One B-rep face of a CAD part: STEP entity #988.
In plain terms, the planar face has unit normal (1, 0, 0).
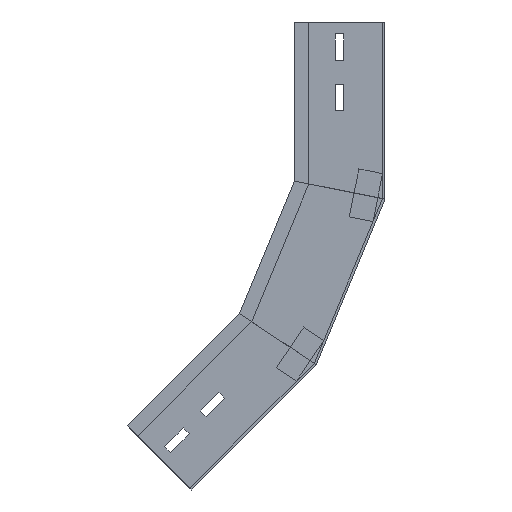
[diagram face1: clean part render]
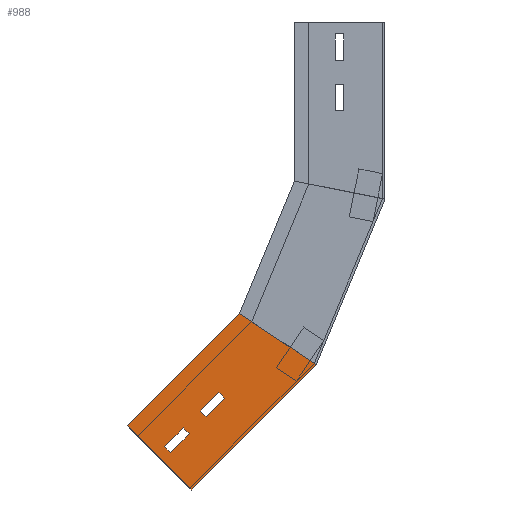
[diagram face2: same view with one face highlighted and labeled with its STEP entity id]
Its self-contained STEP definition (entity closure, numbers rounded to 3 decimals):
#8 = ORIENTED_EDGE ( 'NONE', *, *, #120, .T. ) ;
#31 = VERTEX_POINT ( 'NONE', #232 ) ;
#37 = LINE ( 'NONE', #870, #154 ) ;
#45 = CARTESIAN_POINT ( 'NONE',  ( 0., 0., 0. ) ) ;
#56 = ORIENTED_EDGE ( 'NONE', *, *, #422, .T. ) ;
#59 = CARTESIAN_POINT ( 'NONE',  ( 0., 0., 0. ) ) ;
#78 = DIRECTION ( 'NONE',  ( 0., 0., -1. ) ) ;
#106 = LINE ( 'NONE', #902, #187 ) ;
#120 = EDGE_CURVE ( 'NONE', #785, #31, #37, .T. ) ;
#132 = VECTOR ( 'NONE', #1437, 1000. ) ;
#133 = CARTESIAN_POINT ( 'NONE',  ( 0., 0., 0. ) ) ;
#145 = EDGE_CURVE ( 'NONE', #31, #945, #1111, .T. ) ;
#154 = VECTOR ( 'NONE', #386, 1000. ) ;
#184 = EDGE_CURVE ( 'NONE', #867, #553, #193, .T. ) ;
#185 = EDGE_CURVE ( 'NONE', #945, #330, #884, .T. ) ;
#187 = VECTOR ( 'NONE', #1474, 1000. ) ;
#193 = LINE ( 'NONE', #521, #1269 ) ;
#232 = CARTESIAN_POINT ( 'NONE',  ( 0., 34., -51.505 ) ) ;
#247 = EDGE_CURVE ( 'NONE', #1262, #1181, #1089, .T. ) ;
#288 = PLANE ( 'NONE',  #1145 ) ;
#316 = LINE ( 'NONE', #791, #685 ) ;
#330 = VERTEX_POINT ( 'NONE', #1309 ) ;
#370 = FACE_BOUND ( 'NONE', #1280, .T. ) ;
#386 = DIRECTION ( 'NONE',  ( 0., 0., 1. ) ) ;
#401 = VECTOR ( 'NONE', #714, 1000. ) ;
#422 = EDGE_CURVE ( 'NONE', #553, #1049, #1008, .T. ) ;
#425 = CARTESIAN_POINT ( 'NONE',  ( 0., 41., -9.835 ) ) ;
#487 = ORIENTED_EDGE ( 'NONE', *, *, #583, .F. ) ;
#501 = FACE_OUTER_BOUND ( 'NONE', #1116, .T. ) ;
#507 = DIRECTION ( 'NONE',  ( 0., 1., 0. ) ) ;
#521 = CARTESIAN_POINT ( 'NONE',  ( 0., 41., -31.835 ) ) ;
#524 = DIRECTION ( 'NONE',  ( -1., 0., 0. ) ) ;
#551 = VERTEX_POINT ( 'NONE', #990 ) ;
#553 = VERTEX_POINT ( 'NONE', #1457 ) ;
#583 = EDGE_CURVE ( 'NONE', #1181, #551, #1483, .T. ) ;
#584 = VECTOR ( 'NONE', #507, 1000. ) ;
#596 = EDGE_CURVE ( 'NONE', #730, #867, #106, .T. ) ;
#601 = CARTESIAN_POINT ( 'NONE',  ( 0., 41., -31.835 ) ) ;
#609 = DIRECTION ( 'NONE',  ( 0., -1., 0. ) ) ;
#616 = EDGE_CURVE ( 'NONE', #1049, #730, #316, .T. ) ;
#625 = ORIENTED_EDGE ( 'NONE', *, *, #1005, .T. ) ;
#654 = DIRECTION ( 'NONE',  ( 0., 0., -1. ) ) ;
#656 = ORIENTED_EDGE ( 'NONE', *, *, #185, .T. ) ;
#660 = DIRECTION ( 'NONE',  ( 0., -1., 0. ) ) ;
#664 = ORIENTED_EDGE ( 'NONE', *, *, #247, .F. ) ;
#671 = VECTOR ( 'NONE', #854, 1000. ) ;
#679 = ORIENTED_EDGE ( 'NONE', *, *, #616, .T. ) ;
#683 = VECTOR ( 'NONE', #654, 1000. ) ;
#685 = VECTOR ( 'NONE', #1000, 1000. ) ;
#697 = CARTESIAN_POINT ( 'NONE',  ( 0., 34., -73.505 ) ) ;
#703 = CARTESIAN_POINT ( 'NONE',  ( 0., 0., 0. ) ) ;
#710 = ORIENTED_EDGE ( 'NONE', *, *, #596, .T. ) ;
#714 = DIRECTION ( 'NONE',  ( 0., 0., -1. ) ) ;
#730 = VERTEX_POINT ( 'NONE', #425 ) ;
#782 = ORIENTED_EDGE ( 'NONE', *, *, #184, .T. ) ;
#783 = CARTESIAN_POINT ( 'NONE',  ( 0., 34., -9.835 ) ) ;
#785 = VERTEX_POINT ( 'NONE', #697 ) ;
#791 = CARTESIAN_POINT ( 'NONE',  ( 0., 41., -9.835 ) ) ;
#819 = ORIENTED_EDGE ( 'NONE', *, *, #839, .T. ) ;
#839 = EDGE_CURVE ( 'NONE', #1262, #999, #1286, .T. ) ;
#854 = DIRECTION ( 'NONE',  ( 0., -0.981, -0.195 ) ) ;
#867 = VERTEX_POINT ( 'NONE', #601 ) ;
#870 = CARTESIAN_POINT ( 'NONE',  ( 0., 34., -51.505 ) ) ;
#884 = LINE ( 'NONE', #1447, #683 ) ;
#902 = CARTESIAN_POINT ( 'NONE',  ( 0., 41., -9.835 ) ) ;
#921 = EDGE_CURVE ( 'NONE', #551, #999, #1214, .T. ) ;
#945 = VERTEX_POINT ( 'NONE', #1099 ) ;
#962 = CARTESIAN_POINT ( 'NONE',  ( 0., 28.051, -141.02 ) ) ;
#988 = ADVANCED_FACE ( 'NONE', ( #1448, #501, #370 ), #288, .F. ) ;
#989 = DIRECTION ( 'NONE',  ( 0., 0., 1. ) ) ;
#990 = CARTESIAN_POINT ( 'NONE',  ( 0., 75., -131.682 ) ) ;
#999 = VERTEX_POINT ( 'NONE', #1339 ) ;
#1000 = DIRECTION ( 'NONE',  ( 0., 1., 0. ) ) ;
#1005 = EDGE_CURVE ( 'NONE', #330, #785, #1313, .T. ) ;
#1008 = LINE ( 'NONE', #783, #1481 ) ;
#1022 = CARTESIAN_POINT ( 'NONE',  ( 0., 75., 0. ) ) ;
#1032 = DIRECTION ( 'NONE',  ( 0., 0., 1. ) ) ;
#1049 = VERTEX_POINT ( 'NONE', #1128 ) ;
#1073 = ORIENTED_EDGE ( 'NONE', *, *, #921, .F. ) ;
#1089 = LINE ( 'NONE', #45, #132 ) ;
#1099 = CARTESIAN_POINT ( 'NONE',  ( 0., 41., -51.505 ) ) ;
#1111 = LINE ( 'NONE', #1423, #584 ) ;
#1116 = EDGE_LOOP ( 'NONE', ( #487, #664, #819, #1073 ) ) ;
#1128 = CARTESIAN_POINT ( 'NONE',  ( 0., 34., -9.835 ) ) ;
#1145 = AXIS2_PLACEMENT_3D ( 'NONE', #59, #524, #989 ) ;
#1157 = CARTESIAN_POINT ( 'NONE',  ( 0., 75., 0. ) ) ;
#1181 = VERTEX_POINT ( 'NONE', #1157 ) ;
#1214 = LINE ( 'NONE', #962, #671 ) ;
#1227 = VECTOR ( 'NONE', #78, 1000. ) ;
#1262 = VERTEX_POINT ( 'NONE', #133 ) ;
#1269 = VECTOR ( 'NONE', #660, 1000. ) ;
#1280 = EDGE_LOOP ( 'NONE', ( #679, #710, #782, #56 ) ) ;
#1286 = LINE ( 'NONE', #703, #401 ) ;
#1305 = CARTESIAN_POINT ( 'NONE',  ( 0., 41., -73.505 ) ) ;
#1309 = CARTESIAN_POINT ( 'NONE',  ( 0., 41., -73.505 ) ) ;
#1313 = LINE ( 'NONE', #1305, #1492 ) ;
#1339 = CARTESIAN_POINT ( 'NONE',  ( 0., 0., -146.6 ) ) ;
#1370 = ORIENTED_EDGE ( 'NONE', *, *, #145, .T. ) ;
#1423 = CARTESIAN_POINT ( 'NONE',  ( 0., 41., -51.505 ) ) ;
#1437 = DIRECTION ( 'NONE',  ( 0., 1., 0. ) ) ;
#1447 = CARTESIAN_POINT ( 'NONE',  ( 0., 41., -51.505 ) ) ;
#1448 = FACE_BOUND ( 'NONE', #1475, .T. ) ;
#1457 = CARTESIAN_POINT ( 'NONE',  ( 0., 34., -31.835 ) ) ;
#1474 = DIRECTION ( 'NONE',  ( 0., 0., -1. ) ) ;
#1475 = EDGE_LOOP ( 'NONE', ( #1370, #656, #625, #8 ) ) ;
#1481 = VECTOR ( 'NONE', #1032, 1000. ) ;
#1483 = LINE ( 'NONE', #1022, #1227 ) ;
#1492 = VECTOR ( 'NONE', #609, 1000. ) ;
